# Generated deterministically by seda-macro-lef-normalizer-v1; recipe orfs-asap7-fakeram-m4-v1.
VERSION 5.8 ;
BUSBITCHARS "[]" ;
DIVIDERCHAR "/" ;

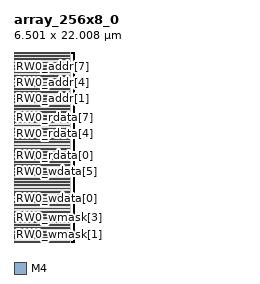
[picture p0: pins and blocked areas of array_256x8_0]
MACRO array_256x8_0
  FOREIGN array_256x8_0 0 0 ;
  CLASS BLOCK ;
  ORIGIN 0 0 ;
  SIZE 6.501 BY 22.008 ;
  SYMMETRY X Y R90 ;
  PIN RW0_wmask[0]
    DIRECTION INPUT ;
    USE SIGNAL ;
    SHAPE ABUTMENT ;
    PORT
      LAYER M4 ;
      RECT 0 0.048 0.024 0.072 ;
    END
  END RW0_wmask[0]
  PIN RW0_wmask[1]
    DIRECTION INPUT ;
    USE SIGNAL ;
    SHAPE ABUTMENT ;
    PORT
      LAYER M4 ;
      RECT 0 0.672 0.024 0.696 ;
    END
  END RW0_wmask[1]
  PIN RW0_wmask[2]
    DIRECTION INPUT ;
    USE SIGNAL ;
    SHAPE ABUTMENT ;
    PORT
      LAYER M4 ;
      RECT 0 1.296 0.024 1.32 ;
    END
  END RW0_wmask[2]
  PIN RW0_wmask[3]
    DIRECTION INPUT ;
    USE SIGNAL ;
    SHAPE ABUTMENT ;
    PORT
      LAYER M4 ;
      RECT 0 1.92 0.024 1.944 ;
    END
  END RW0_wmask[3]
  PIN RW0_wmask[4]
    DIRECTION INPUT ;
    USE SIGNAL ;
    SHAPE ABUTMENT ;
    PORT
      LAYER M4 ;
      RECT 0 2.544 0.024 2.568 ;
    END
  END RW0_wmask[4]
  PIN RW0_wmask[5]
    DIRECTION INPUT ;
    USE SIGNAL ;
    SHAPE ABUTMENT ;
    PORT
      LAYER M4 ;
      RECT 0 3.168 0.024 3.192 ;
    END
  END RW0_wmask[5]
  PIN RW0_wmask[6]
    DIRECTION INPUT ;
    USE SIGNAL ;
    SHAPE ABUTMENT ;
    PORT
      LAYER M4 ;
      RECT 0 3.792 0.024 3.816 ;
    END
  END RW0_wmask[6]
  PIN RW0_wmask[7]
    DIRECTION INPUT ;
    USE SIGNAL ;
    SHAPE ABUTMENT ;
    PORT
      LAYER M4 ;
      RECT 0 4.416 0.024 4.44 ;
    END
  END RW0_wmask[7]
  PIN RW0_wdata[0]
    DIRECTION INPUT ;
    USE SIGNAL ;
    SHAPE ABUTMENT ;
    PORT
      LAYER M4 ;
      RECT 0 5.04 0.024 5.064 ;
    END
  END RW0_wdata[0]
  PIN RW0_wdata[1]
    DIRECTION INPUT ;
    USE SIGNAL ;
    SHAPE ABUTMENT ;
    PORT
      LAYER M4 ;
      RECT 0 5.664 0.024 5.688 ;
    END
  END RW0_wdata[1]
  PIN RW0_wdata[2]
    DIRECTION INPUT ;
    USE SIGNAL ;
    SHAPE ABUTMENT ;
    PORT
      LAYER M4 ;
      RECT 0 6.288 0.024 6.312 ;
    END
  END RW0_wdata[2]
  PIN RW0_wdata[3]
    DIRECTION INPUT ;
    USE SIGNAL ;
    SHAPE ABUTMENT ;
    PORT
      LAYER M4 ;
      RECT 0 6.912 0.024 6.936 ;
    END
  END RW0_wdata[3]
  PIN RW0_wdata[4]
    DIRECTION INPUT ;
    USE SIGNAL ;
    SHAPE ABUTMENT ;
    PORT
      LAYER M4 ;
      RECT 0 7.536 0.024 7.56 ;
    END
  END RW0_wdata[4]
  PIN RW0_wdata[5]
    DIRECTION INPUT ;
    USE SIGNAL ;
    SHAPE ABUTMENT ;
    PORT
      LAYER M4 ;
      RECT 0 8.16 0.024 8.184 ;
    END
  END RW0_wdata[5]
  PIN RW0_wdata[6]
    DIRECTION INPUT ;
    USE SIGNAL ;
    SHAPE ABUTMENT ;
    PORT
      LAYER M4 ;
      RECT 0 8.784 0.024 8.808 ;
    END
  END RW0_wdata[6]
  PIN RW0_wdata[7]
    DIRECTION INPUT ;
    USE SIGNAL ;
    SHAPE ABUTMENT ;
    PORT
      LAYER M4 ;
      RECT 0 9.408 0.024 9.432 ;
    END
  END RW0_wdata[7]
  PIN RW0_rdata[0]
    DIRECTION OUTPUT ;
    USE SIGNAL ;
    SHAPE ABUTMENT ;
    PORT
      LAYER M4 ;
      RECT 0 10.032 0.024 10.056 ;
    END
  END RW0_rdata[0]
  PIN RW0_rdata[1]
    DIRECTION OUTPUT ;
    USE SIGNAL ;
    SHAPE ABUTMENT ;
    PORT
      LAYER M4 ;
      RECT 0 10.656 0.024 10.68 ;
    END
  END RW0_rdata[1]
  PIN RW0_rdata[2]
    DIRECTION OUTPUT ;
    USE SIGNAL ;
    SHAPE ABUTMENT ;
    PORT
      LAYER M4 ;
      RECT 0 11.28 0.024 11.304 ;
    END
  END RW0_rdata[2]
  PIN RW0_rdata[3]
    DIRECTION OUTPUT ;
    USE SIGNAL ;
    SHAPE ABUTMENT ;
    PORT
      LAYER M4 ;
      RECT 0 11.904 0.024 11.928 ;
    END
  END RW0_rdata[3]
  PIN RW0_rdata[4]
    DIRECTION OUTPUT ;
    USE SIGNAL ;
    SHAPE ABUTMENT ;
    PORT
      LAYER M4 ;
      RECT 0 12.528 0.024 12.552 ;
    END
  END RW0_rdata[4]
  PIN RW0_rdata[5]
    DIRECTION OUTPUT ;
    USE SIGNAL ;
    SHAPE ABUTMENT ;
    PORT
      LAYER M4 ;
      RECT 0 13.152 0.024 13.176 ;
    END
  END RW0_rdata[5]
  PIN RW0_rdata[6]
    DIRECTION OUTPUT ;
    USE SIGNAL ;
    SHAPE ABUTMENT ;
    PORT
      LAYER M4 ;
      RECT 0 13.776 0.024 13.8 ;
    END
  END RW0_rdata[6]
  PIN RW0_rdata[7]
    DIRECTION OUTPUT ;
    USE SIGNAL ;
    SHAPE ABUTMENT ;
    PORT
      LAYER M4 ;
      RECT 0 14.4 0.024 14.424 ;
    END
  END RW0_rdata[7]
  PIN RW0_addr[0]
    DIRECTION INPUT ;
    USE SIGNAL ;
    SHAPE ABUTMENT ;
    PORT
      LAYER M4 ;
      RECT 0 15.024 0.024 15.048 ;
    END
  END RW0_addr[0]
  PIN RW0_addr[1]
    DIRECTION INPUT ;
    USE SIGNAL ;
    SHAPE ABUTMENT ;
    PORT
      LAYER M4 ;
      RECT 0 15.648 0.024 15.672 ;
    END
  END RW0_addr[1]
  PIN RW0_addr[2]
    DIRECTION INPUT ;
    USE SIGNAL ;
    SHAPE ABUTMENT ;
    PORT
      LAYER M4 ;
      RECT 0 16.272 0.024 16.296 ;
    END
  END RW0_addr[2]
  PIN RW0_addr[3]
    DIRECTION INPUT ;
    USE SIGNAL ;
    SHAPE ABUTMENT ;
    PORT
      LAYER M4 ;
      RECT 0 16.896 0.024 16.92 ;
    END
  END RW0_addr[3]
  PIN RW0_addr[4]
    DIRECTION INPUT ;
    USE SIGNAL ;
    SHAPE ABUTMENT ;
    PORT
      LAYER M4 ;
      RECT 0 17.52 0.024 17.544 ;
    END
  END RW0_addr[4]
  PIN RW0_addr[5]
    DIRECTION INPUT ;
    USE SIGNAL ;
    SHAPE ABUTMENT ;
    PORT
      LAYER M4 ;
      RECT 0 18.144 0.024 18.168 ;
    END
  END RW0_addr[5]
  PIN RW0_addr[6]
    DIRECTION INPUT ;
    USE SIGNAL ;
    SHAPE ABUTMENT ;
    PORT
      LAYER M4 ;
      RECT 0 18.768 0.024 18.792 ;
    END
  END RW0_addr[6]
  PIN RW0_addr[7]
    DIRECTION INPUT ;
    USE SIGNAL ;
    SHAPE ABUTMENT ;
    PORT
      LAYER M4 ;
      RECT 0 19.392 0.024 19.416 ;
    END
  END RW0_addr[7]
  PIN RW0_wmode
    DIRECTION INPUT ;
    USE SIGNAL ;
    SHAPE ABUTMENT ;
    PORT
      LAYER M4 ;
      RECT 0 20.016 0.024 20.04 ;
    END
  END RW0_wmode
  PIN RW0_en
    DIRECTION INPUT ;
    USE SIGNAL ;
    SHAPE ABUTMENT ;
    PORT
      LAYER M4 ;
      RECT 0 20.64 0.024 20.664 ;
    END
  END RW0_en
  PIN RW0_clk
    DIRECTION INPUT ;
    USE SIGNAL ;
    SHAPE ABUTMENT ;
    PORT
      LAYER M4 ;
      RECT 0 21.264 0.024 21.288 ;
    END
  END RW0_clk
  PIN VSS
    DIRECTION INOUT ;
    USE GROUND ;
    PORT
      LAYER M4 ;
      RECT 0.048 0 6.453 0.096 ;
      RECT 0.048 0.768 6.453 0.864 ;
      RECT 0.048 1.536 6.453 1.632 ;
      RECT 0.048 2.304 6.453 2.4 ;
      RECT 0.048 3.072 6.453 3.168 ;
      RECT 0.048 3.84 6.453 3.936 ;
      RECT 0.048 4.608 6.453 4.704 ;
      RECT 0.048 5.376 6.453 5.472 ;
      RECT 0.048 6.144 6.453 6.24 ;
      RECT 0.048 6.912 6.453 7.008 ;
      RECT 0.048 7.68 6.453 7.776 ;
      RECT 0.048 8.448 6.453 8.544 ;
      RECT 0.048 9.216 6.453 9.312 ;
      RECT 0.048 9.984 6.453 10.08 ;
      RECT 0.048 10.752 6.453 10.848 ;
      RECT 0.048 11.52 6.453 11.616 ;
      RECT 0.048 12.288 6.453 12.384 ;
      RECT 0.048 13.056 6.453 13.152 ;
      RECT 0.048 13.824 6.453 13.92 ;
      RECT 0.048 14.592 6.453 14.688 ;
      RECT 0.048 15.36 6.453 15.456 ;
      RECT 0.048 16.128 6.453 16.224 ;
      RECT 0.048 16.896 6.453 16.992 ;
      RECT 0.048 17.664 6.453 17.76 ;
      RECT 0.048 18.432 6.453 18.528 ;
      RECT 0.048 19.2 6.453 19.296 ;
      RECT 0.048 19.968 6.453 20.064 ;
      RECT 0.048 20.736 6.453 20.832 ;
      RECT 0.048 21.504 6.453 21.6 ;
    END
  END VSS
  PIN VDD
    DIRECTION INOUT ;
    USE POWER ;
    PORT
      LAYER M4 ;
      RECT 0.048 0.384 6.453 0.48 ;
      RECT 0.048 1.152 6.453 1.248 ;
      RECT 0.048 1.92 6.453 2.016 ;
      RECT 0.048 2.688 6.453 2.784 ;
      RECT 0.048 3.456 6.453 3.552 ;
      RECT 0.048 4.224 6.453 4.32 ;
      RECT 0.048 4.992 6.453 5.088 ;
      RECT 0.048 5.76 6.453 5.856 ;
      RECT 0.048 6.528 6.453 6.624 ;
      RECT 0.048 7.296 6.453 7.392 ;
      RECT 0.048 8.064 6.453 8.16 ;
      RECT 0.048 8.832 6.453 8.928 ;
      RECT 0.048 9.6 6.453 9.696 ;
      RECT 0.048 10.368 6.453 10.464 ;
      RECT 0.048 11.136 6.453 11.232 ;
      RECT 0.048 11.904 6.453 12 ;
      RECT 0.048 12.672 6.453 12.768 ;
      RECT 0.048 13.44 6.453 13.536 ;
      RECT 0.048 14.208 6.453 14.304 ;
      RECT 0.048 14.976 6.453 15.072 ;
      RECT 0.048 15.744 6.453 15.84 ;
      RECT 0.048 16.512 6.453 16.608 ;
      RECT 0.048 17.28 6.453 17.376 ;
      RECT 0.048 18.048 6.453 18.144 ;
      RECT 0.048 18.816 6.453 18.912 ;
      RECT 0.048 19.584 6.453 19.68 ;
      RECT 0.048 20.352 6.453 20.448 ;
      RECT 0.048 21.12 6.453 21.216 ;
      RECT 0.048 21.888 6.453 21.984 ;
    END
  END VDD
  OBS
    LAYER M1 ;
    RECT 0 0 6.501 22.008 ;
    LAYER M2 ;
    RECT 0 0 6.501 22.008 ;
    LAYER M3 ;
    RECT 0 0 6.501 22.008 ;
  END
END array_256x8_0

END LIBRARY
